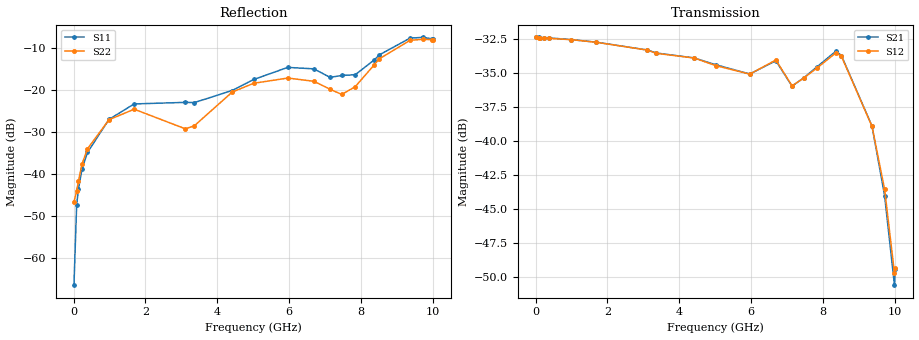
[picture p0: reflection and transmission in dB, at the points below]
! Device ID: PE43704
! Dir: z:\PE43704\PE43704_Char_1_20130516\PE43704\AMB\3p400V\31p50dB
! Serial: 14
! Insertion: A
! Impedance: 50 ohm
! Temp: Amb
! VDD: 3.400V
! Attenuation Step: 31.50dB
! IDD: 1.139487e-01mA
#  Hz  S  RI  R  50
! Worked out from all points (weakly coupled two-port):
!   401 points, 10 MHz to 10.01 GHz, reference 50 ohm
!   highest |S21| = -32.37 dB at 10 MHz (marker M1); lowest = -50.6 dB at 9.985 GHz (marker M2)
!   lowest |S11| = -66.4 dB at 10 MHz (marker M3), VSWR 1.00, Z = 50 + j0.044 ohm
!   |S11| at or under -10 dB: start of sweep to 8.739 GHz
!   |S22| runs from -46.6 to -7.9 dB; largest |S21 - S12| = 0.00065
!   S11 on the Smith chart (normalised r, x): 10 MHz: 1.00, +0.00; 7.46 GHz: 0.78, +0.14; 8.51 GHz: 0.81, +0.45; 9.36 GHz: 0.54, +0.48; 10.01 GHz: 0.46, +0.27
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1e7  -0.000182 0.00044  0.0241 -0.000115  0.0241 -7.25e-05  -0.00466 0.000466
8.5e7  -7.95e-05 0.00429  0.0241 -0.000495  0.024 -0.000492  -0.00432 0.00447
1.35e8  -0.000253 0.00661  0.024 -0.000785  0.024 -0.000763  -0.00452 0.00693
2.35e8  -0.00194 0.0113  0.024 -0.00129  0.024 -0.00128  -0.00582 0.0118
3.85e8  -0.00502 0.0173  0.0239 -0.00215  0.0238 -0.00213  -0.00871 0.0179
9.85e8  -0.0331 0.0299  0.0231 -0.0051  0.0231 -0.00507  -0.0328 0.0296
1.685e9  -0.0664 0.0152  0.0216 -0.00833  0.0216 -0.00828  -0.0573 0.0139
3.11e9  -0.0708 -0.00652  0.0171 -0.0133  0.017 -0.0134  -0.0333 0.00878
3.36e9  -0.0707 -0.000794  0.0159 -0.0139  0.0159 -0.0138  -0.0333 0.0171
4.41e9  -0.0882 0.0436  0.0128 -0.0157  0.0129 -0.0156  -0.0749 0.0569
5.01e9  -0.1119 0.072  0.0112 -0.0155  0.0111 -0.0154  -0.1056 0.0569
5.96e9  -0.1593 0.0949  0.00812 -0.0157  0.00808 -0.0157  -0.1312 0.0441
6.685e9  -0.159 0.0801  0.00723 -0.0184  0.00734 -0.0185  -0.1217 0.035
7.135e9  -0.129 0.0574  0.00374 -0.0155  0.00352 -0.0156  -0.0913 0.0454
7.46e9  -0.1183 0.0898  0.00414 -0.0166  0.0044 -0.0165  -0.0662 0.0585
7.835e9  -0.0722 0.1332  0.00437 -0.0183  0.00433 -0.0181  -0.052 0.096
8.36e9  -0.0406 0.223  -0.00267 -0.0213  -0.0027 -0.021  -0.072 0.1843
8.51e9  -0.044 0.2579  -0.00517 -0.02  -0.00501 -0.0199  -0.0867 0.2183
9.36e9  -0.1882 0.3677  -0.0087 -0.00733  -0.00874 -0.00724  -0.2507 0.2976
9.71e9  -0.2692 0.3245  -0.00467 -0.00425  -0.00529 -0.00406  -0.3252 0.2331
9.985e9  -0.3192 0.2492  -0.000884 -0.00282  -0.000753 -0.00319  -0.3684 0.1444
1.001e10  -0.3248 0.2412  -0.000733 -0.00332  -0.000401 -0.00338  -0.3724 0.1359
